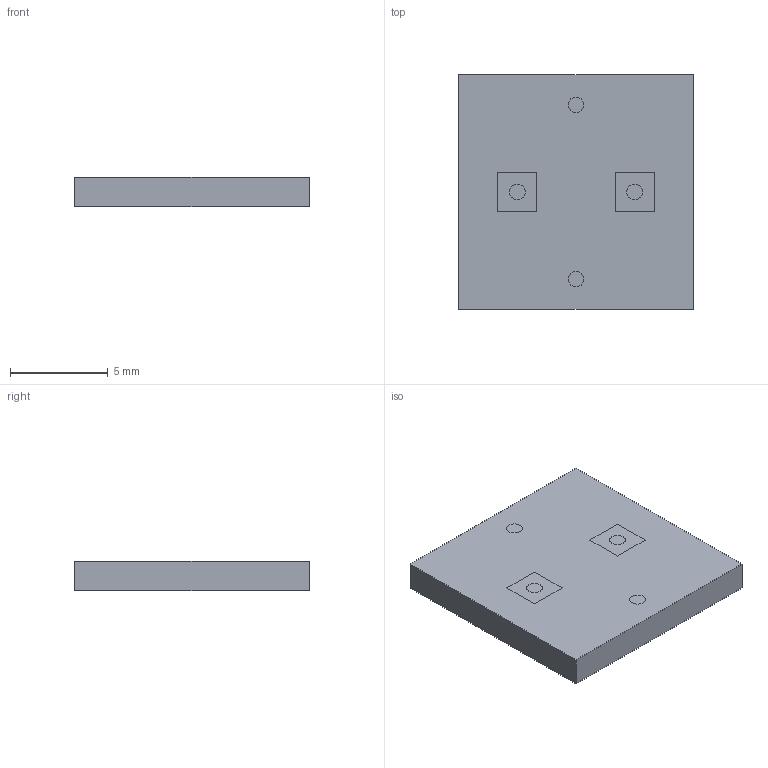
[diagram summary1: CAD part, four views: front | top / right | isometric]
STEP (ISO 10303-21) file: header records copied from the file, then geometry measured from it (millimetres).
FILE_DESCRIPTION(('Open CASCADE Model'),'2;1');
FILE_NAME('Open CASCADE Shape Model','2026-11-27T14:00:10',('Author'),( 'Open CASCADE'),'Open CASCADE STEP processor 7.9','Open CASCADE 7.9' ,'Unknown');
FILE_SCHEMA(('AUTOMOTIVE_DESIGN { 1 0 10303 214 1 1 1 1 }'));
Length unit declared in the file: millimetre
Products named in the file (3): manifold_N29; fluid; solid
Assembly tree (2 placements, depth 2):
  manifold_N29
    fluid
    solid
Bounding box: 12 x 12 x 1.5 mm (x, y, z)
Volume: 216 mm3; surface area: 1189 mm2
Topology: 2 solids, 2 shells, 746 faces, 2402 edges, 1430 vertices
Faces by surface type: plane 738, cylinder 8
Full cylindrical faces by diameter (mm): 0.8 x8
Entity records: 57174 total; most frequent: CARTESIAN_POINT 9995, DIRECTION 8584, LINE 6902, VECTOR 6902, ORIENTED_EDGE 4804, PCURVE 4804, DEFINITIONAL_REPRESENTATION 4804, EDGE_CURVE 2402
One B-rep face of a CAD part: STEP entity #30688.
In plain terms, the planar face has unit normal (-1, 0, 0).
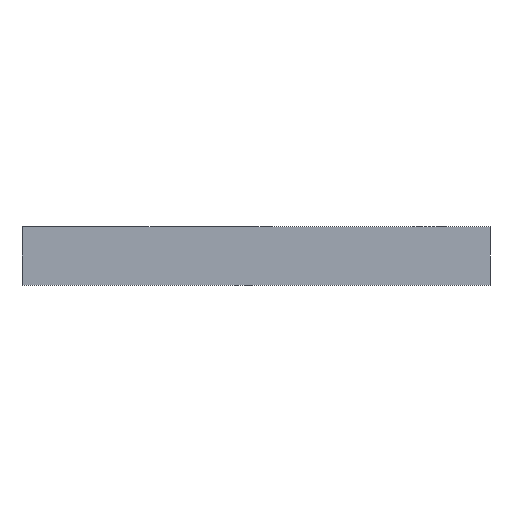
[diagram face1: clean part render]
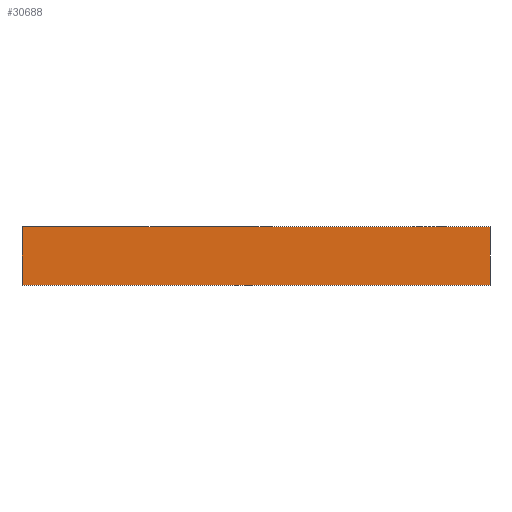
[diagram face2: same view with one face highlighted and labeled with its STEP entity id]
Its self-contained STEP definition (entity closure, numbers rounded to 3 decimals):
#30688 = ADVANCED_FACE('',(#30689),#30703,.F.);
#30689 = FACE_BOUND('',#30690,.F.);
#30690 = EDGE_LOOP('',(#30691,#30726,#30754,#30782));
#30691 = ORIENTED_EDGE('',*,*,#30692,.F.);
#30692 = EDGE_CURVE('',#30693,#30695,#30697,.T.);
#30693 = VERTEX_POINT('',#30694);
#30694 = CARTESIAN_POINT('',(0.,0.,0.));
#30695 = VERTEX_POINT('',#30696);
#30696 = CARTESIAN_POINT('',(0.,0.,1.5));
#30697 = SURFACE_CURVE('',#30698,(#30702,#30714),.PCURVE_S1.);
#30698 = LINE('',#30699,#30700);
#30699 = CARTESIAN_POINT('',(0.,0.,0.));
#30700 = VECTOR('',#30701,1.);
#30701 = DIRECTION('',(0.,0.,1.));
#30702 = PCURVE('',#30703,#30708);
#30703 = PLANE('',#30704);
#30704 = AXIS2_PLACEMENT_3D('',#30705,#30706,#30707);
#30705 = CARTESIAN_POINT('',(0.,0.,0.));
#30706 = DIRECTION('',(1.,0.,-0.));
#30707 = DIRECTION('',(0.,0.,1.));
#30708 = DEFINITIONAL_REPRESENTATION('',(#30709),#30713);
#30709 = LINE('',#30710,#30711);
#30710 = CARTESIAN_POINT('',(0.,0.));
#30711 = VECTOR('',#30712,1.);
#30712 = DIRECTION('',(1.,0.));
#30713 = ( GEOMETRIC_REPRESENTATION_CONTEXT(2) 
PARAMETRIC_REPRESENTATION_CONTEXT() REPRESENTATION_CONTEXT('2D SPACE',''
  ) );
#30714 = PCURVE('',#30715,#30720);
#30715 = PLANE('',#30716);
#30716 = AXIS2_PLACEMENT_3D('',#30717,#30718,#30719);
#30717 = CARTESIAN_POINT('',(0.,0.,0.));
#30718 = DIRECTION('',(-0.,1.,0.));
#30719 = DIRECTION('',(0.,0.,1.));
#30720 = DEFINITIONAL_REPRESENTATION('',(#30721),#30725);
#30721 = LINE('',#30722,#30723);
#30722 = CARTESIAN_POINT('',(0.,0.));
#30723 = VECTOR('',#30724,1.);
#30724 = DIRECTION('',(1.,0.));
#30725 = ( GEOMETRIC_REPRESENTATION_CONTEXT(2) 
PARAMETRIC_REPRESENTATION_CONTEXT() REPRESENTATION_CONTEXT('2D SPACE',''
  ) );
#30726 = ORIENTED_EDGE('',*,*,#30727,.T.);
#30727 = EDGE_CURVE('',#30693,#30728,#30730,.T.);
#30728 = VERTEX_POINT('',#30729);
#30729 = CARTESIAN_POINT('',(0.,12.,0.));
#30730 = SURFACE_CURVE('',#30731,(#30735,#30742),.PCURVE_S1.);
#30731 = LINE('',#30732,#30733);
#30732 = CARTESIAN_POINT('',(0.,0.,0.));
#30733 = VECTOR('',#30734,1.);
#30734 = DIRECTION('',(-0.,1.,0.));
#30735 = PCURVE('',#30703,#30736);
#30736 = DEFINITIONAL_REPRESENTATION('',(#30737),#30741);
#30737 = LINE('',#30738,#30739);
#30738 = CARTESIAN_POINT('',(0.,0.));
#30739 = VECTOR('',#30740,1.);
#30740 = DIRECTION('',(0.,-1.));
#30741 = ( GEOMETRIC_REPRESENTATION_CONTEXT(2) 
PARAMETRIC_REPRESENTATION_CONTEXT() REPRESENTATION_CONTEXT('2D SPACE',''
  ) );
#30742 = PCURVE('',#30743,#30748);
#30743 = PLANE('',#30744);
#30744 = AXIS2_PLACEMENT_3D('',#30745,#30746,#30747);
#30745 = CARTESIAN_POINT('',(0.,0.,0.));
#30746 = DIRECTION('',(0.,0.,1.));
#30747 = DIRECTION('',(1.,0.,-0.));
#30748 = DEFINITIONAL_REPRESENTATION('',(#30749),#30753);
#30749 = LINE('',#30750,#30751);
#30750 = CARTESIAN_POINT('',(0.,0.));
#30751 = VECTOR('',#30752,1.);
#30752 = DIRECTION('',(0.,1.));
#30753 = ( GEOMETRIC_REPRESENTATION_CONTEXT(2) 
PARAMETRIC_REPRESENTATION_CONTEXT() REPRESENTATION_CONTEXT('2D SPACE',''
  ) );
#30754 = ORIENTED_EDGE('',*,*,#30755,.T.);
#30755 = EDGE_CURVE('',#30728,#30756,#30758,.T.);
#30756 = VERTEX_POINT('',#30757);
#30757 = CARTESIAN_POINT('',(0.,12.,1.5));
#30758 = SURFACE_CURVE('',#30759,(#30763,#30770),.PCURVE_S1.);
#30759 = LINE('',#30760,#30761);
#30760 = CARTESIAN_POINT('',(0.,12.,0.));
#30761 = VECTOR('',#30762,1.);
#30762 = DIRECTION('',(0.,0.,1.));
#30763 = PCURVE('',#30703,#30764);
#30764 = DEFINITIONAL_REPRESENTATION('',(#30765),#30769);
#30765 = LINE('',#30766,#30767);
#30766 = CARTESIAN_POINT('',(0.,-12.));
#30767 = VECTOR('',#30768,1.);
#30768 = DIRECTION('',(1.,0.));
#30769 = ( GEOMETRIC_REPRESENTATION_CONTEXT(2) 
PARAMETRIC_REPRESENTATION_CONTEXT() REPRESENTATION_CONTEXT('2D SPACE',''
  ) );
#30770 = PCURVE('',#30771,#30776);
#30771 = PLANE('',#30772);
#30772 = AXIS2_PLACEMENT_3D('',#30773,#30774,#30775);
#30773 = CARTESIAN_POINT('',(0.,12.,0.));
#30774 = DIRECTION('',(-0.,1.,0.));
#30775 = DIRECTION('',(0.,0.,1.));
#30776 = DEFINITIONAL_REPRESENTATION('',(#30777),#30781);
#30777 = LINE('',#30778,#30779);
#30778 = CARTESIAN_POINT('',(0.,0.));
#30779 = VECTOR('',#30780,1.);
#30780 = DIRECTION('',(1.,0.));
#30781 = ( GEOMETRIC_REPRESENTATION_CONTEXT(2) 
PARAMETRIC_REPRESENTATION_CONTEXT() REPRESENTATION_CONTEXT('2D SPACE',''
  ) );
#30782 = ORIENTED_EDGE('',*,*,#30783,.F.);
#30783 = EDGE_CURVE('',#30695,#30756,#30784,.T.);
#30784 = SURFACE_CURVE('',#30785,(#30789,#30796),.PCURVE_S1.);
#30785 = LINE('',#30786,#30787);
#30786 = CARTESIAN_POINT('',(0.,0.,1.5));
#30787 = VECTOR('',#30788,1.);
#30788 = DIRECTION('',(-0.,1.,0.));
#30789 = PCURVE('',#30703,#30790);
#30790 = DEFINITIONAL_REPRESENTATION('',(#30791),#30795);
#30791 = LINE('',#30792,#30793);
#30792 = CARTESIAN_POINT('',(1.5,0.));
#30793 = VECTOR('',#30794,1.);
#30794 = DIRECTION('',(0.,-1.));
#30795 = ( GEOMETRIC_REPRESENTATION_CONTEXT(2) 
PARAMETRIC_REPRESENTATION_CONTEXT() REPRESENTATION_CONTEXT('2D SPACE',''
  ) );
#30796 = PCURVE('',#30797,#30802);
#30797 = PLANE('',#30798);
#30798 = AXIS2_PLACEMENT_3D('',#30799,#30800,#30801);
#30799 = CARTESIAN_POINT('',(0.,0.,1.5));
#30800 = DIRECTION('',(0.,0.,1.));
#30801 = DIRECTION('',(1.,0.,-0.));
#30802 = DEFINITIONAL_REPRESENTATION('',(#30803),#30807);
#30803 = LINE('',#30804,#30805);
#30804 = CARTESIAN_POINT('',(0.,0.));
#30805 = VECTOR('',#30806,1.);
#30806 = DIRECTION('',(0.,1.));
#30807 = ( GEOMETRIC_REPRESENTATION_CONTEXT(2) 
PARAMETRIC_REPRESENTATION_CONTEXT() REPRESENTATION_CONTEXT('2D SPACE',''
  ) );
